VERSION 5.7 ;
  NOWIREEXTENSIONATPIN ON ;
  DIVIDERCHAR "/" ;
  BUSBITCHARS "[]" ;
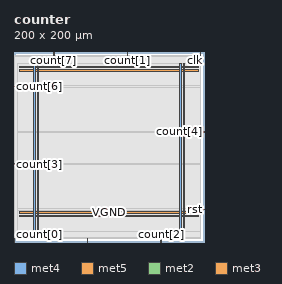
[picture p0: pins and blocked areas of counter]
MACRO counter
  CLASS BLOCK ;
  FOREIGN counter ;
  ORIGIN 0.000 0.000 ;
  SIZE 200.000 BY 200.000 ;
  PIN VGND
    DIRECTION INOUT ;
    USE GROUND ;
    PORT
      LAYER met4 ;
        RECT 24.340 10.640 25.940 187.920 ;
    END
    PORT
      LAYER met4 ;
        RECT 177.940 10.640 179.540 187.920 ;
    END
    PORT
      LAYER met5 ;
        RECT 5.280 30.030 194.360 31.630 ;
    END
    PORT
      LAYER met5 ;
        RECT 5.280 183.210 194.360 184.810 ;
    END
  END VGND
  PIN VPWR
    DIRECTION INOUT ;
    USE POWER ;
    PORT
      LAYER met4 ;
        RECT 21.040 10.640 22.640 187.920 ;
    END
    PORT
      LAYER met4 ;
        RECT 174.640 10.640 176.240 187.920 ;
    END
    PORT
      LAYER met5 ;
        RECT 5.280 26.730 194.360 28.330 ;
    END
    PORT
      LAYER met5 ;
        RECT 5.280 179.910 194.360 181.510 ;
    END
  END VPWR
  PIN clk
    DIRECTION INPUT ;
    USE SIGNAL ;
    ANTENNAGATEAREA 0.852000 ;
    PORT
      LAYER met2 ;
        RECT 196.510 196.000 196.790 200.000 ;
    END
  END clk
  PIN count[0]
    DIRECTION OUTPUT TRISTATE ;
    USE SIGNAL ;
    ANTENNADIFFAREA 0.795200 ;
    PORT
      LAYER met2 ;
        RECT 0.090 0.000 0.370 4.000 ;
    END
  END count[0]
  PIN count[1]
    DIRECTION OUTPUT TRISTATE ;
    USE SIGNAL ;
    ANTENNADIFFAREA 0.795200 ;
    PORT
      LAYER met2 ;
        RECT 119.230 196.000 119.510 200.000 ;
    END
  END count[1]
  PIN count[2]
    DIRECTION OUTPUT TRISTATE ;
    USE SIGNAL ;
    ANTENNADIFFAREA 0.795200 ;
    PORT
      LAYER met2 ;
        RECT 154.650 0.000 154.930 4.000 ;
    END
  END count[2]
  PIN count[3]
    DIRECTION OUTPUT TRISTATE ;
    USE SIGNAL ;
    ANTENNADIFFAREA 0.795200 ;
    PORT
      LAYER met3 ;
        RECT 0.000 81.640 4.000 82.240 ;
    END
  END count[3]
  PIN count[4]
    DIRECTION OUTPUT TRISTATE ;
    USE SIGNAL ;
    ANTENNADIFFAREA 0.795200 ;
    PORT
      LAYER met3 ;
        RECT 196.000 115.640 200.000 116.240 ;
    END
  END count[4]
  PIN count[5]
    DIRECTION OUTPUT TRISTATE ;
    USE SIGNAL ;
    ANTENNADIFFAREA 0.795200 ;
    PORT
      LAYER met2 ;
        RECT 77.370 0.000 77.650 4.000 ;
    END
  END count[5]
  PIN count[6]
    DIRECTION OUTPUT TRISTATE ;
    USE SIGNAL ;
    ANTENNADIFFAREA 0.795200 ;
    PORT
      LAYER met3 ;
        RECT 0.000 163.240 4.000 163.840 ;
    END
  END count[6]
  PIN count[7]
    DIRECTION OUTPUT TRISTATE ;
    USE SIGNAL ;
    ANTENNADIFFAREA 0.795200 ;
    PORT
      LAYER met2 ;
        RECT 41.950 196.000 42.230 200.000 ;
    END
  END count[7]
  PIN rst
    DIRECTION INPUT ;
    USE SIGNAL ;
    ANTENNAGATEAREA 0.247500 ;
    PORT
      LAYER met3 ;
        RECT 196.000 34.040 200.000 34.640 ;
    END
  END rst
  OBS
      LAYER li1 ;
        RECT 5.520 10.795 194.120 187.765 ;
      LAYER met1 ;
        RECT 0.070 10.640 194.510 187.920 ;
      LAYER met2 ;
        RECT 0.100 195.720 41.670 196.000 ;
        RECT 42.510 195.720 118.950 196.000 ;
        RECT 119.790 195.720 196.230 196.000 ;
        RECT 0.100 4.280 196.790 195.720 ;
        RECT 0.650 4.000 77.090 4.280 ;
        RECT 77.930 4.000 154.370 4.280 ;
        RECT 155.210 4.000 196.790 4.280 ;
      LAYER met3 ;
        RECT 3.990 164.240 196.815 187.845 ;
        RECT 4.400 162.840 196.815 164.240 ;
        RECT 3.990 116.640 196.815 162.840 ;
        RECT 3.990 115.240 195.600 116.640 ;
        RECT 3.990 82.640 196.815 115.240 ;
        RECT 4.400 81.240 196.815 82.640 ;
        RECT 3.990 35.040 196.815 81.240 ;
        RECT 3.990 33.640 195.600 35.040 ;
        RECT 3.990 10.715 196.815 33.640 ;
  END
END counter
END LIBRARY

